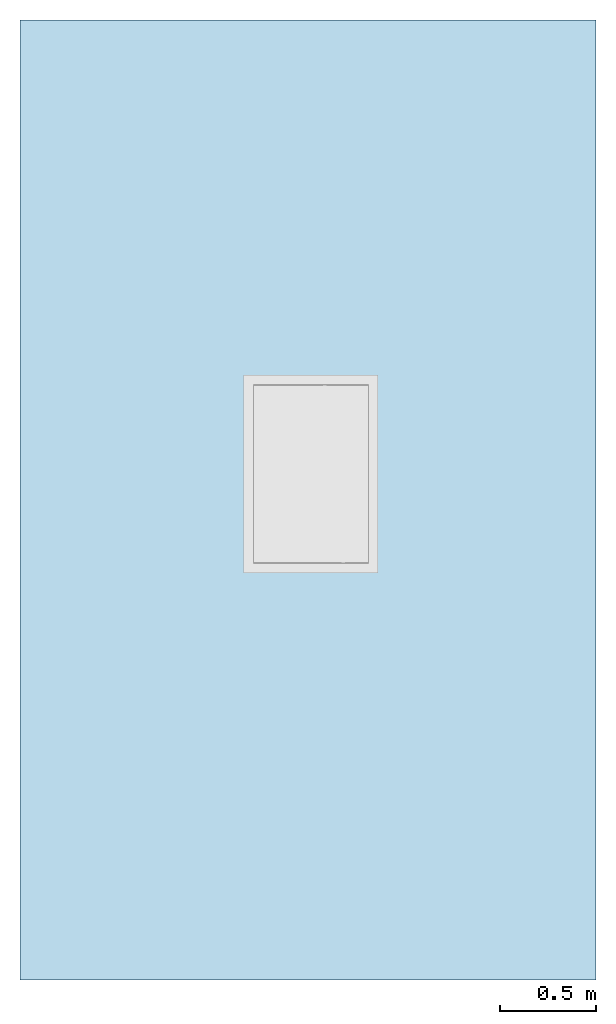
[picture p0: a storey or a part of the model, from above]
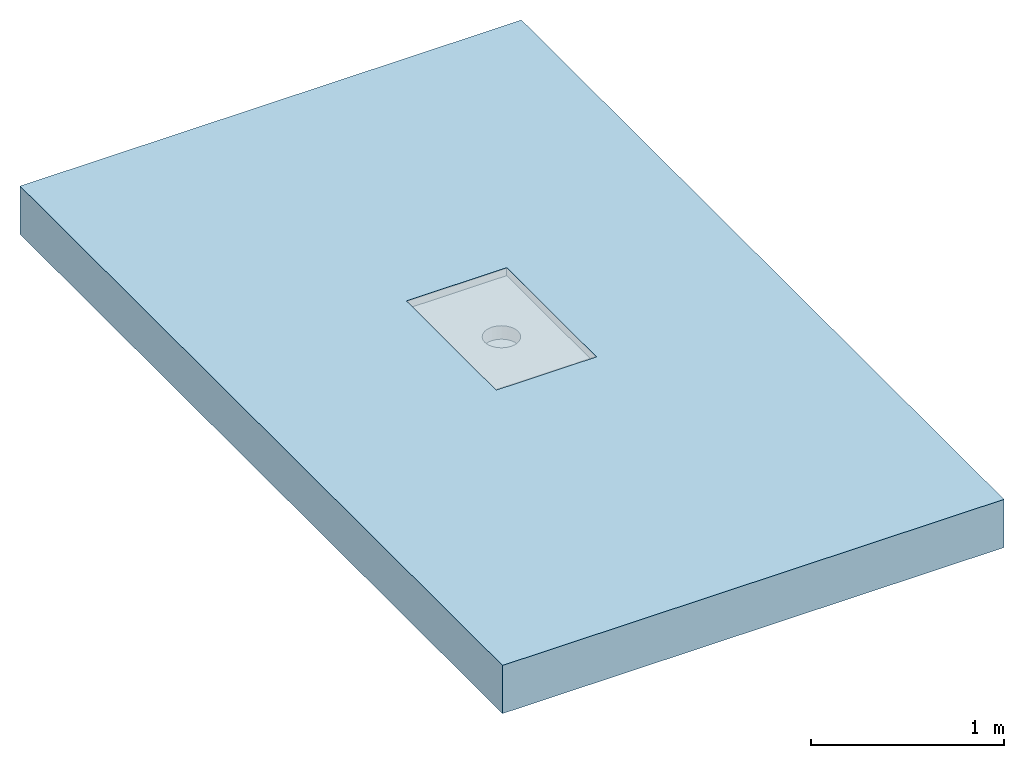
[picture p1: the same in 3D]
Properties of the parts of a building model (IFC2X3)

# File
Description: ViewDefinition [CoordinationView]
File name: Project Number
Time: 2016-11-22T10:08:27
Written by: The EXPRESS Data Manager Version 5.01.0100.02.64mod : 6 Jun 2012
Made in: 20130308_1515(x64) - Exporter 2014.0.2013.0308 - Default UI
Comment: STEP Physical File produced by: The EXPRESS Data Manager Version 5.01.0100.02.64mod : 6 Jun 2012 * Module: EDMstepFileFactory/EDMstandAlone * Creation date: Tue Nov 22 10:08:27 2016 * Host: IN-BLR-PC-0012 * Database: C:\Users\pakumar\AppData\Local\Temp\{EAD75F9B-FE44-440D-AE50-D78E60B0ECF4}\ifc * Database version: 5507 * Database creation date: Tue Nov 22 10:08:26 2016 * Schema: IFC2X3 * Model: DataRepository.ifc * Model creation date: Tue Nov 22 10:08:26 2016 * Header model: DataRepository.ifc_HeaderModel * Header model creation date: Tue Nov 22 10:08:26 2016 * EDMuser: sdai-user * EDMgroup: sdai-group * License ID and type: 5605 : Permanent license. Expiry date: * EDMstepFileFactory options: 020000

# IfcProject, Project Number
LongName: Project Name; Phase: Project Status

# IfcSite, Default
RefLatitude: 42, 21, 30, 344238; RefLongitude: -71, -3, -35, -194702; RefElevation: 0 mm

# IfcBuilding
Pset_BuildingCommon - NumberOfStoreys: 1
Other - Client Name: Owner; Project Name: Project Name; Project Number: Project Number; Project Status: Project Status; Project Address: Enter address here; Project Issue Date: Issue Date

# IfcBuildingStorey, Level 1
LongName: Level 1; Elevation: 0 mm
Constraints - Elevation Base: Project Base Point; Elevation: 0 mm
Graphics - Symbol: Level Head - Circle: Level Head - Circle; Color: 0; Line Pattern: Grid Line 1/2"; Line Weight: 1; Symbol at End 2 Default: yes; Symbol at End 1 Default: no
Dimensions - Computation Height: 0 mm
Identity Data - Building Story: yes; Structural: no; Name: Level 1

# IfcFlowTerminal: 416763 - Hygienic Extended Channel - with Gully 218 - 900mm LG - 600mm Wide, ACO Tray Channel - Hygienic - Extended - 600mm Wide:416763 - Hygienic Extended Channel - with Gully 218 - 900mm LG - 600mm Wide:451573
In: Level 1
Material: Stainless Steel AISI 304, Stainless Steel AISI 304 - Grating
Construction - Detail - Outlet 200: yes; Grating: yes; 416876 - 568 x 298mm - Mesh Grating - L15 - Stainless Steel 1.4301: yes; 416838 - 568 x 298mm - Ladder Grating - R50 - Stainless Steel 1.4301: no; 416896 - 568 x 298mm - Mesh Grating - L15 - Stainless Steel 1.4301: no
Mechanical - System Classification: Sanitary
Phasing - Phase Created: New Construction
Constraints - Level: Level: Level 1
Identity Data - Mark: 34; E-mail Technical: abdtechnical@aco.co.uk; Watermark2: This file is water marked and users are prohibited to reproduce, adapt, distribute this information.; Watermarked With: BIM Manager Premium Suite.; Address: ACO Business Centre, Caxton Road, Bedford, MK41 0LF; Telephone: +44 (0)1462 816666; E-mail Sales: abdcommercial@aco.co.uk; Website: www.acobd.com; Fax: +44 (0)1462 851490; Watermarked By: www.acobd.com; Watermark1: This file is the property of ACO Technologies PLC.; Manufacturer: ACO Building Drainage; Cost: 0
Pset_ManufacturerTypeInformation - Manufacturer: ACO Building Drainage
Dimensions - End Connection Plate End: -900 mm; End Connection Plate Start: -870 mm; Number of gratings: 3; Grating Void Cut Length: 500 mm; Floor Cut Void Height: 62.8 mm; Outlet: 200 mm; Grating Height: 21 mm; Depth: 29 mm; x: -915 mm; Length Channel: -870 mm; Inside Outlet Rad: 98 mm; Spigot Distance: 450 mm; Invert Depth: 50 mm; Outside Outlet Rad: 100 mm; Grating Length: 298 mm; End Plate: 900 mm; Endplate Position: 900 mm
Other - Hygienic Standard Channel - 900mm LG - 600mm Wide: yes; Number mesh: 19; Spigot Outlets Channels: yes; Hygienic Standard Channel - 1200mm LG - 600mm Wide: no; Invert Depth Detail: 51.5 mm; Hygienic Standard Channel - 600mm LG - 600mm Wide: no; Flow: 0.155385 m3/s
General - Product Code: 416763; Product Standard: EN 1253 / EN 1672 / EN ISO 14159; Installation guidelines: http://issuu.com/acobuildingdrainage/docs/aco_hygiene_first_catalogue/17?e=0; Foul air trap seal Material: NBR; Product Description: ACO Hygiene First Extended Kitchen Tray Channel 600 x 930 / 200 Dia Outlet & Foul Air Trap; Channel Material: Stainless steel 1.4301 (EN 10088); Channel Dimension: 600 x 930; Foul air trap Recycled material content: 0%; Product Range: ACO Hygiene First; Channel Colour: passivated stainless steel surface ( matt grey); Maintenance guidelines: http://issuu.com/acobuildingdrainage/docs/aco_hygiene_first_catalogue/17?e=0; Price: POA - contact ACO; Foul air trap seal Colour: Black; Load Class: A15 - C250 (EN 1253); Product Type: Extended Kitchen Tray Channel; Foul air trap Recyclable: Fully recyclable; Channel Recyclable: Fully recyclable; Weight (Kg): 12.3; Outlet Diameter (mm): 200; Channel Recycled material content: 20 - 30 %
Model Properties - Grating Product Code 416896: Load Class L 15 (EN 1253) - Mesh Grate - Stainless steel 1.4301 (EN 10088) - 568 x 298 - 4.7kg; Grating Product Code 416876: Load Class L 15 (EN 1253) - Mesh Grate - Stainless steel 1.4301 (EN 10088) - 568 x 298 - 4.6kg; Grating Product Code 416838: Load Class R 50 (EN 1253) - Ladder Grate - Stainless steel 1.4301 (EN 10088) - 568 x 298 - 10.7kg

# IfcOpeningElement: Recess
In: Level 1
Structural - Structural: no; Enable Analytical Model: no
Dimensions - Perimeter: 16000 mm; Area: 161.459 ft2; Volume: 160.379 ft3; Thickness: 304.8 mm
Phasing - Phase Created: New Construction
Constraints - Related to Mass: no; Height Offset From Level: 0 mm; Level: Level: Level 1; Room Bounding: yes
Construction - Default Thickness: 304.8 mm; Function: Interior
Identity Data - Assembly Code: B1010; Assembly Description: Floor Construction
Analytical Properties - Roughness: 3; Absorptance: 0.7
Graphics - Coarse Scale Fill Color: 0

# IfcSlab: Floor:Generic - 12", Floor:Generic - 12":184145
In: Level 1
PredefinedType: FLOOR; Material: Default Floor 304.8 mm
Structural - Structural: no; Enable Analytical Model: no
Dimensions - Perimeter: 16000 mm; Area: 161.459 ft2; Volume: 160.379 ft3; Thickness: 304.8 mm
Phasing - Phase Created: New Construction
Constraints - Related to Mass: no; Height Offset From Level: 0 mm; Level: Level: Level 1; Room Bounding: yes
Pset_SlabCommon - Reference: Generic - 12"; IsExternal: no; LoadBearing: yes
Construction - Default Thickness: 304.8 mm; Function: Interior
Identity Data - Assembly Code: B1010; Assembly Description: Floor Construction
Analytical Properties - Roughness: 3; Absorptance: 0.7
Graphics - Coarse Scale Fill Color: 0
